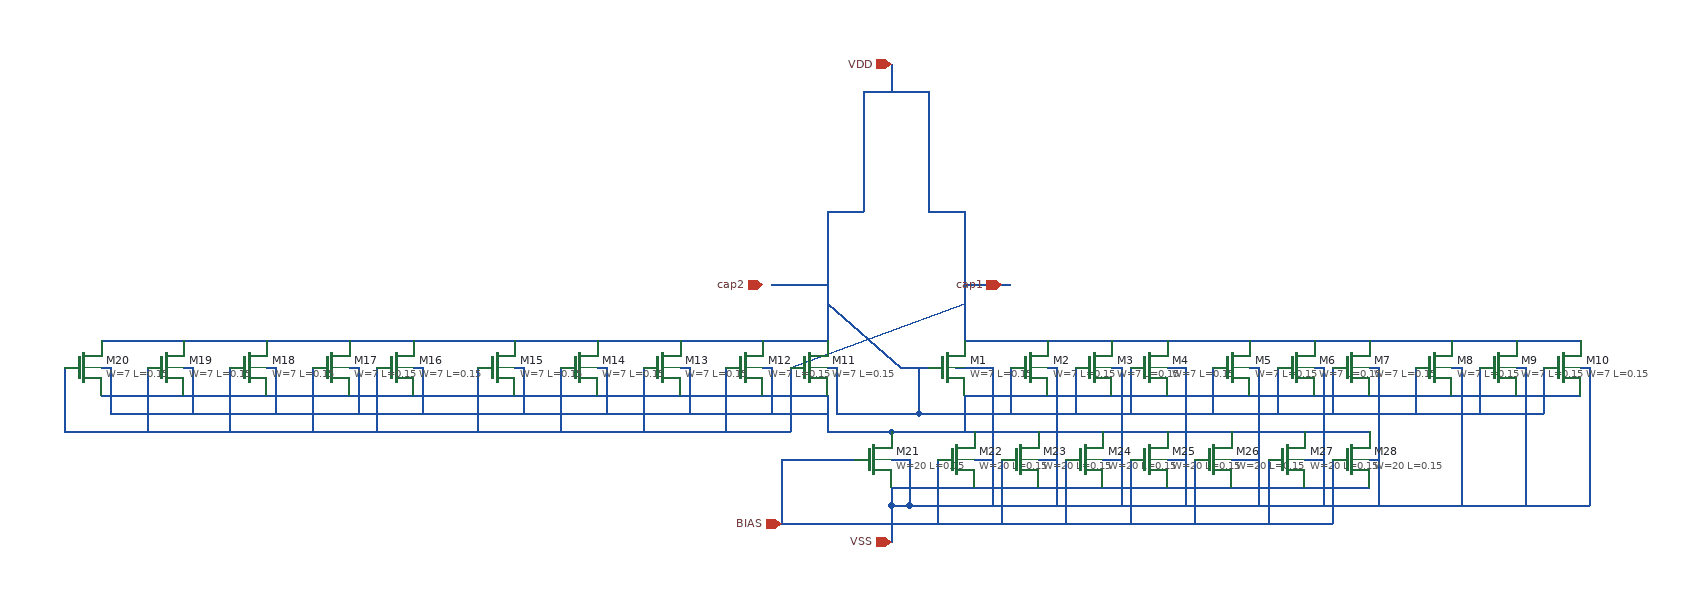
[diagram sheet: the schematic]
v {xschem version=3.0.0 file_version=1.2 }
G {}
K {}
V {}
S {}
E {}
N -10 100 60 100 {
lab=#net1}
N -10 60 -10 100 {
lab=#net1}
N 60 100 140 100 {
lab=#net1}
N 140 60 140 100 {
lab=#net1}
N 140 -80 140 0 {
lab=cap1}
N 60 -300 60 -270 {
lab=VDD}
N -10 -80 -10 0 {
lab=cap1}
N 70 30 100 30 {
lab=cap1}
N -60 130 20 130 {
lab=BIAS}
N -10 30 0 30 {
lab=cap1}
N 60 180 80 180 {
lab=VSS}
N 130 30 140 30 {
lab=VSS}
N 140 30 170 30 {
lab=VSS}
N 0 30 0 80 {
lab=cap1}
N 30 -270 30 -220 {
lab=cap1}
N 30 -160 30 -140 {
lab=cap1}
N -10 -140 30 -140 {
lab=cap1}
N 100 -140 140 -140 {
lab=cap1}
N -10 -40 70 30 {
lab=cap1}
N -10 -140 -10 -80 {
lab=cap1}
N 140 -140 140 -80 {
lab=cap1}
N -50 30 140 -40 {
lab=cap1}
N 30 -220 30 -160 {
lab=cap1}
N 30 -270 100 -270 {
lab=cap1}
N 140 -60 190 -60 {
lab=cap1}
N -70 -60 -10 -60 {
lab=cap1}
N 100 -270 100 -140 {
lab=cap1}
N 140 0 810 -0 {
lab=cap1}
N 140 60 810 60 {
lab=#net1}
N 230 30 240 30 {
lab=VSS}
N 240 30 240 180 {
lab=VSS}
N 300 30 310 30 {
lab=VSS}
N 310 30 310 180 {
lab=VSS}
N 380 30 380 180 {
lab=VSS}
N 360 30 380 30 {
lab=VSS}
N 450 30 460 30 {
lab=VSS}
N 460 30 460 180 {
lab=VSS}
N 520 30 530 30 {
lab=VSS}
N 530 30 530 180 {
lab=VSS}
N 580 30 590 30 {
lab=VSS}
N 590 30 590 180 {
lab=VSS}
N 670 30 680 30 {
lab=VSS}
N 680 30 680 180 {
lab=VSS}
N 740 30 750 30 {
lab=VSS}
N 750 30 750 180 {
lab=VSS}
N 810 30 820 30 {
lab=VSS}
N 820 30 820 180 {
lab=VSS}
N 80 180 820 180 {
lab=VSS}
N 90 30 90 80 {
lab=cap1}
N 170 30 170 180 {
lab=VSS}
N 90 80 770 80 {
lab=cap1}
N 770 30 770 80 {
lab=cap1}
N 700 30 700 80 {
lab=cap1}
N 630 30 630 80 {
lab=cap1}
N 540 30 540 80 {
lab=cap1}
N 480 30 480 80 {
lab=cap1}
N 410 30 410 80 {
lab=cap1}
N 320 30 320 80 {
lab=cap1}
N 260 30 260 80 {
lab=cap1}
N 190 30 190 80 {
lab=cap1}
N -800 -0 -10 -0 {
lab=cap1}
N -800 60 -10 60 {
lab=#net1}
N 0 80 90 80 {
lab=cap1}
N -80 30 -70 30 {
lab=#net1}
N -70 30 -70 80 {
lab=#net1}
N -170 30 -160 30 {
lab=#net1}
N -160 30 -160 80 {
lab=#net1}
N -260 30 -250 30 {
lab=#net1}
N -250 30 -250 80 {
lab=#net1}
N -350 30 -340 30 {
lab=#net1}
N -340 30 -340 80 {
lab=#net1}
N -460 30 -450 30 {
lab=#net1}
N -450 30 -450 80 {
lab=#net1}
N -530 30 -520 30 {
lab=#net1}
N -520 30 -520 80 {
lab=#net1}
N -620 30 -610 30 {
lab=#net1}
N -610 30 -610 80 {
lab=#net1}
N -710 30 -700 30 {
lab=#net1}
N -700 30 -700 80 {
lab=#net1}
N -800 30 -790 30 {
lab=#net1}
N -790 30 -790 80 {
lab=#net1}
N -790 80 -10 80 {
lab=#net1}
N -50 30 -50 100 {
lab=cap1}
N -840 100 -50 100 {
lab=cap1}
N -840 30 -840 100 {
lab=cap1}
N -750 30 -750 100 {
lab=cap1}
N -660 30 -660 100 {
lab=cap1}
N -570 30 -570 100 {
lab=cap1}
N -500 30 -500 100 {
lab=cap1}
N -390 30 -390 100 {
lab=cap1}
N -300 30 -300 100 {
lab=cap1}
N -210 30 -210 100 {
lab=cap1}
N -120 30 -120 100 {
lab=cap1}
N -60 130 -60 200 {
lab=BIAS}
N -60 200 540 200 {
lab=BIAS}
N 540 130 540 200 {
lab=BIAS}
N 470 130 470 200 {
lab=BIAS}
N 390 130 390 200 {
lab=BIAS}
N 320 130 320 200 {
lab=BIAS}
N 250 130 250 200 {
lab=BIAS}
N 180 130 180 200 {
lab=BIAS}
N 110 130 110 200 {
lab=BIAS}
N 60 100 580 100 {
lab=#net1}
N 580 130 590 130 {
lab=VSS}
N 60 160 60 180 {
lab=VSS}
N 60 180 60 220 {
lab=VSS}
N 60 160 580 160 {
lab=VSS}
N 510 130 530 130 {
lab=VSS}
N 430 130 460 130 {
lab=VSS}
N 360 130 380 130 {
lab=VSS}
N 290 130 310 130 {
lab=VSS}
N 220 130 240 130 {
lab=VSS}
N 150 130 170 130 {
lab=VSS}
N 60 130 80 130 {
lab=VSS}
N 80 130 80 180 {
lab=VSS}
C {sky130_fd_pr/nfet_01v8_lvt.sym} 40 130 0 0 {name=M21
L=0.15
W=20
nf=20
mult=1
ad="'int((nf+1)/2) * W/nf * 0.29'" 
pd="'2*int((nf+1)/2) * (W/nf + 0.29)'"
as="'int((nf+2)/2) * W/nf * 0.29'" 
ps="'2*int((nf+2)/2) * (W/nf + 0.29)'"
nrd="'0.29 / W'" nrs="'0.29 / W'"
sa=0 sb=0 sd=0
model=nfet_01v8_lvt
spiceprefix=X
}
C {sky130_fd_pr/nfet_01v8_lvt.sym} -30 30 0 0 {name=M11
L=0.15
W=7
nf=7
mult=1
ad="'int((nf+1)/2) * W/nf * 0.29'" 
pd="'2*int((nf+1)/2) * (W/nf + 0.29)'"
as="'int((nf+2)/2) * W/nf * 0.29'" 
ps="'2*int((nf+2)/2) * (W/nf + 0.29)'"
nrd="'0.29 / W'" nrs="'0.29 / W'"
sa=0 sb=0 sd=0
model=nfet_01v8_lvt
spiceprefix=X
}
C {sky130_fd_pr/nfet_01v8_lvt.sym} 120 30 0 0 {name=M1
L=0.15
W=7
nf=7
mult=1
ad="'int((nf+1)/2) * W/nf * 0.29'" 
pd="'2*int((nf+1)/2) * (W/nf + 0.29)'"
as="'int((nf+2)/2) * W/nf * 0.29'" 
ps="'2*int((nf+2)/2) * (W/nf + 0.29)'"
nrd="'0.29 / W'" nrs="'0.29 / W'"
sa=0 sb=0 sd=0
model=nfet_01v8_lvt
spiceprefix=X
}
C {iopin.sym} 180 -60 0 0 {name=p1 lab=cap1}
C {iopin.sym} -80 -60 0 0 {name=p2 lab=cap2}
C {ipin.sym} 60 -300 0 0 {name=p3 lab=VDD}
C {ipin.sym} -60 200 0 0 {name=p4 lab=BIAS}
C {ipin.sym} 60 220 0 0 {name=p5 lab=VSS}
C {sky130_fd_pr/nfet_01v8_lvt.sym} 210 30 0 0 {name=M2
L=0.15
W=7
nf=7
mult=1
ad="'int((nf+1)/2) * W/nf * 0.29'" 
pd="'2*int((nf+1)/2) * (W/nf + 0.29)'"
as="'int((nf+2)/2) * W/nf * 0.29'" 
ps="'2*int((nf+2)/2) * (W/nf + 0.29)'"
nrd="'0.29 / W'" nrs="'0.29 / W'"
sa=0 sb=0 sd=0
model=nfet_01v8_lvt
spiceprefix=X
}
C {sky130_fd_pr/nfet_01v8_lvt.sym} 280 30 0 0 {name=M3
L=0.15
W=7
nf=7
mult=1
ad="'int((nf+1)/2) * W/nf * 0.29'" 
pd="'2*int((nf+1)/2) * (W/nf + 0.29)'"
as="'int((nf+2)/2) * W/nf * 0.29'" 
ps="'2*int((nf+2)/2) * (W/nf + 0.29)'"
nrd="'0.29 / W'" nrs="'0.29 / W'"
sa=0 sb=0 sd=0
model=nfet_01v8_lvt
spiceprefix=X
}
C {sky130_fd_pr/nfet_01v8_lvt.sym} 340 30 0 0 {name=M4
L=0.15
W=7
nf=7
mult=1
ad="'int((nf+1)/2) * W/nf * 0.29'" 
pd="'2*int((nf+1)/2) * (W/nf + 0.29)'"
as="'int((nf+2)/2) * W/nf * 0.29'" 
ps="'2*int((nf+2)/2) * (W/nf + 0.29)'"
nrd="'0.29 / W'" nrs="'0.29 / W'"
sa=0 sb=0 sd=0
model=nfet_01v8_lvt
spiceprefix=X
}
C {sky130_fd_pr/nfet_01v8_lvt.sym} 430 30 0 0 {name=M5
L=0.15
W=7
nf=7
mult=1
ad="'int((nf+1)/2) * W/nf * 0.29'" 
pd="'2*int((nf+1)/2) * (W/nf + 0.29)'"
as="'int((nf+2)/2) * W/nf * 0.29'" 
ps="'2*int((nf+2)/2) * (W/nf + 0.29)'"
nrd="'0.29 / W'" nrs="'0.29 / W'"
sa=0 sb=0 sd=0
model=nfet_01v8_lvt
spiceprefix=X
}
C {sky130_fd_pr/nfet_01v8_lvt.sym} 500 30 0 0 {name=M6
L=0.15
W=7
nf=7
mult=1
ad="'int((nf+1)/2) * W/nf * 0.29'" 
pd="'2*int((nf+1)/2) * (W/nf + 0.29)'"
as="'int((nf+2)/2) * W/nf * 0.29'" 
ps="'2*int((nf+2)/2) * (W/nf + 0.29)'"
nrd="'0.29 / W'" nrs="'0.29 / W'"
sa=0 sb=0 sd=0
model=nfet_01v8_lvt
spiceprefix=X
}
C {sky130_fd_pr/nfet_01v8_lvt.sym} 560 30 0 0 {name=M7
L=0.15
W=7
nf=7
mult=1
ad="'int((nf+1)/2) * W/nf * 0.29'" 
pd="'2*int((nf+1)/2) * (W/nf + 0.29)'"
as="'int((nf+2)/2) * W/nf * 0.29'" 
ps="'2*int((nf+2)/2) * (W/nf + 0.29)'"
nrd="'0.29 / W'" nrs="'0.29 / W'"
sa=0 sb=0 sd=0
model=nfet_01v8_lvt
spiceprefix=X
}
C {sky130_fd_pr/nfet_01v8_lvt.sym} 650 30 0 0 {name=M8
L=0.15
W=7
nf=7
mult=1
ad="'int((nf+1)/2) * W/nf * 0.29'" 
pd="'2*int((nf+1)/2) * (W/nf + 0.29)'"
as="'int((nf+2)/2) * W/nf * 0.29'" 
ps="'2*int((nf+2)/2) * (W/nf + 0.29)'"
nrd="'0.29 / W'" nrs="'0.29 / W'"
sa=0 sb=0 sd=0
model=nfet_01v8_lvt
spiceprefix=X
}
C {sky130_fd_pr/nfet_01v8_lvt.sym} 720 30 0 0 {name=M9
L=0.15
W=7
nf=7
mult=1
ad="'int((nf+1)/2) * W/nf * 0.29'" 
pd="'2*int((nf+1)/2) * (W/nf + 0.29)'"
as="'int((nf+2)/2) * W/nf * 0.29'" 
ps="'2*int((nf+2)/2) * (W/nf + 0.29)'"
nrd="'0.29 / W'" nrs="'0.29 / W'"
sa=0 sb=0 sd=0
model=nfet_01v8_lvt
spiceprefix=X
}
C {sky130_fd_pr/nfet_01v8_lvt.sym} 790 30 0 0 {name=M10
L=0.15
W=7
nf=7
mult=1
ad="'int((nf+1)/2) * W/nf * 0.29'" 
pd="'2*int((nf+1)/2) * (W/nf + 0.29)'"
as="'int((nf+2)/2) * W/nf * 0.29'" 
ps="'2*int((nf+2)/2) * (W/nf + 0.29)'"
nrd="'0.29 / W'" nrs="'0.29 / W'"
sa=0 sb=0 sd=0
model=nfet_01v8_lvt
spiceprefix=X
}
C {sky130_fd_pr/nfet_01v8_lvt.sym} 130 130 0 0 {name=M22
L=0.15
W=20
nf=20
mult=1
ad="'int((nf+1)/2) * W/nf * 0.29'" 
pd="'2*int((nf+1)/2) * (W/nf + 0.29)'"
as="'int((nf+2)/2) * W/nf * 0.29'" 
ps="'2*int((nf+2)/2) * (W/nf + 0.29)'"
nrd="'0.29 / W'" nrs="'0.29 / W'"
sa=0 sb=0 sd=0
model=nfet_01v8_lvt
spiceprefix=X
}
C {sky130_fd_pr/nfet_01v8_lvt.sym} 200 130 0 0 {name=M23
L=0.15
W=20
nf=20
mult=1
ad="'int((nf+1)/2) * W/nf * 0.29'" 
pd="'2*int((nf+1)/2) * (W/nf + 0.29)'"
as="'int((nf+2)/2) * W/nf * 0.29'" 
ps="'2*int((nf+2)/2) * (W/nf + 0.29)'"
nrd="'0.29 / W'" nrs="'0.29 / W'"
sa=0 sb=0 sd=0
model=nfet_01v8_lvt
spiceprefix=X
}
C {sky130_fd_pr/nfet_01v8_lvt.sym} 270 130 0 0 {name=M24
L=0.15
W=20
nf=20
mult=1
ad="'int((nf+1)/2) * W/nf * 0.29'" 
pd="'2*int((nf+1)/2) * (W/nf + 0.29)'"
as="'int((nf+2)/2) * W/nf * 0.29'" 
ps="'2*int((nf+2)/2) * (W/nf + 0.29)'"
nrd="'0.29 / W'" nrs="'0.29 / W'"
sa=0 sb=0 sd=0
model=nfet_01v8_lvt
spiceprefix=X
}
C {sky130_fd_pr/nfet_01v8_lvt.sym} 340 130 0 0 {name=M25
L=0.15
W=20
nf=20
mult=1
ad="'int((nf+1)/2) * W/nf * 0.29'" 
pd="'2*int((nf+1)/2) * (W/nf + 0.29)'"
as="'int((nf+2)/2) * W/nf * 0.29'" 
ps="'2*int((nf+2)/2) * (W/nf + 0.29)'"
nrd="'0.29 / W'" nrs="'0.29 / W'"
sa=0 sb=0 sd=0
model=nfet_01v8_lvt
spiceprefix=X
}
C {sky130_fd_pr/nfet_01v8_lvt.sym} 410 130 0 0 {name=M26
L=0.15
W=20
nf=20
mult=1
ad="'int((nf+1)/2) * W/nf * 0.29'" 
pd="'2*int((nf+1)/2) * (W/nf + 0.29)'"
as="'int((nf+2)/2) * W/nf * 0.29'" 
ps="'2*int((nf+2)/2) * (W/nf + 0.29)'"
nrd="'0.29 / W'" nrs="'0.29 / W'"
sa=0 sb=0 sd=0
model=nfet_01v8_lvt
spiceprefix=X
}
C {sky130_fd_pr/nfet_01v8_lvt.sym} 490 130 0 0 {name=M27
L=0.15
W=20
nf=20
mult=1
ad="'int((nf+1)/2) * W/nf * 0.29'" 
pd="'2*int((nf+1)/2) * (W/nf + 0.29)'"
as="'int((nf+2)/2) * W/nf * 0.29'" 
ps="'2*int((nf+2)/2) * (W/nf + 0.29)'"
nrd="'0.29 / W'" nrs="'0.29 / W'"
sa=0 sb=0 sd=0
model=nfet_01v8_lvt
spiceprefix=X
}
C {sky130_fd_pr/nfet_01v8_lvt.sym} 560 130 0 0 {name=M28
L=0.15
W=20
nf=20
mult=1
ad="'int((nf+1)/2) * W/nf * 0.29'" 
pd="'2*int((nf+1)/2) * (W/nf + 0.29)'"
as="'int((nf+2)/2) * W/nf * 0.29'" 
ps="'2*int((nf+2)/2) * (W/nf + 0.29)'"
nrd="'0.29 / W'" nrs="'0.29 / W'"
sa=0 sb=0 sd=0
model=nfet_01v8_lvt
spiceprefix=X
}
C {sky130_fd_pr/nfet_01v8_lvt.sym} -100 30 0 0 {name=M12
L=0.15
W=7
nf=7
mult=1
ad="'int((nf+1)/2) * W/nf * 0.29'" 
pd="'2*int((nf+1)/2) * (W/nf + 0.29)'"
as="'int((nf+2)/2) * W/nf * 0.29'" 
ps="'2*int((nf+2)/2) * (W/nf + 0.29)'"
nrd="'0.29 / W'" nrs="'0.29 / W'"
sa=0 sb=0 sd=0
model=nfet_01v8_lvt
spiceprefix=X
}
C {sky130_fd_pr/nfet_01v8_lvt.sym} -190 30 0 0 {name=M13
L=0.15
W=7
nf=7
mult=1
ad="'int((nf+1)/2) * W/nf * 0.29'" 
pd="'2*int((nf+1)/2) * (W/nf + 0.29)'"
as="'int((nf+2)/2) * W/nf * 0.29'" 
ps="'2*int((nf+2)/2) * (W/nf + 0.29)'"
nrd="'0.29 / W'" nrs="'0.29 / W'"
sa=0 sb=0 sd=0
model=nfet_01v8_lvt
spiceprefix=X
}
C {sky130_fd_pr/nfet_01v8_lvt.sym} -280 30 0 0 {name=M14
L=0.15
W=7
nf=7
mult=1
ad="'int((nf+1)/2) * W/nf * 0.29'" 
pd="'2*int((nf+1)/2) * (W/nf + 0.29)'"
as="'int((nf+2)/2) * W/nf * 0.29'" 
ps="'2*int((nf+2)/2) * (W/nf + 0.29)'"
nrd="'0.29 / W'" nrs="'0.29 / W'"
sa=0 sb=0 sd=0
model=nfet_01v8_lvt
spiceprefix=X
}
C {sky130_fd_pr/nfet_01v8_lvt.sym} -370 30 0 0 {name=M15
L=0.15
W=7
nf=7
mult=1
ad="'int((nf+1)/2) * W/nf * 0.29'" 
pd="'2*int((nf+1)/2) * (W/nf + 0.29)'"
as="'int((nf+2)/2) * W/nf * 0.29'" 
ps="'2*int((nf+2)/2) * (W/nf + 0.29)'"
nrd="'0.29 / W'" nrs="'0.29 / W'"
sa=0 sb=0 sd=0
model=nfet_01v8_lvt
spiceprefix=X
}
C {sky130_fd_pr/nfet_01v8_lvt.sym} -480 30 0 0 {name=M16
L=0.15
W=7
nf=7
mult=1
ad="'int((nf+1)/2) * W/nf * 0.29'" 
pd="'2*int((nf+1)/2) * (W/nf + 0.29)'"
as="'int((nf+2)/2) * W/nf * 0.29'" 
ps="'2*int((nf+2)/2) * (W/nf + 0.29)'"
nrd="'0.29 / W'" nrs="'0.29 / W'"
sa=0 sb=0 sd=0
model=nfet_01v8_lvt
spiceprefix=X
}
C {sky130_fd_pr/nfet_01v8_lvt.sym} -550 30 0 0 {name=M17
L=0.15
W=7
nf=7
mult=1
ad="'int((nf+1)/2) * W/nf * 0.29'" 
pd="'2*int((nf+1)/2) * (W/nf + 0.29)'"
as="'int((nf+2)/2) * W/nf * 0.29'" 
ps="'2*int((nf+2)/2) * (W/nf + 0.29)'"
nrd="'0.29 / W'" nrs="'0.29 / W'"
sa=0 sb=0 sd=0
model=nfet_01v8_lvt
spiceprefix=X
}
C {sky130_fd_pr/nfet_01v8_lvt.sym} -640 30 0 0 {name=M18
L=0.15
W=7
nf=7
mult=1
ad="'int((nf+1)/2) * W/nf * 0.29'" 
pd="'2*int((nf+1)/2) * (W/nf + 0.29)'"
as="'int((nf+2)/2) * W/nf * 0.29'" 
ps="'2*int((nf+2)/2) * (W/nf + 0.29)'"
nrd="'0.29 / W'" nrs="'0.29 / W'"
sa=0 sb=0 sd=0
model=nfet_01v8_lvt
spiceprefix=X
}
C {sky130_fd_pr/nfet_01v8_lvt.sym} -730 30 0 0 {name=M19
L=0.15
W=7
nf=7
mult=1
ad="'int((nf+1)/2) * W/nf * 0.29'" 
pd="'2*int((nf+1)/2) * (W/nf + 0.29)'"
as="'int((nf+2)/2) * W/nf * 0.29'" 
ps="'2*int((nf+2)/2) * (W/nf + 0.29)'"
nrd="'0.29 / W'" nrs="'0.29 / W'"
sa=0 sb=0 sd=0
model=nfet_01v8_lvt
spiceprefix=X
}
C {sky130_fd_pr/nfet_01v8_lvt.sym} -820 30 0 0 {name=M20
L=0.15
W=7
nf=7
mult=1
ad="'int((nf+1)/2) * W/nf * 0.29'" 
pd="'2*int((nf+1)/2) * (W/nf + 0.29)'"
as="'int((nf+2)/2) * W/nf * 0.29'" 
ps="'2*int((nf+2)/2) * (W/nf + 0.29)'"
nrd="'0.29 / W'" nrs="'0.29 / W'"
sa=0 sb=0 sd=0
model=nfet_01v8_lvt
spiceprefix=X
}
